VERSION 5.7 ;
BUSBITCHARS "[]" ;
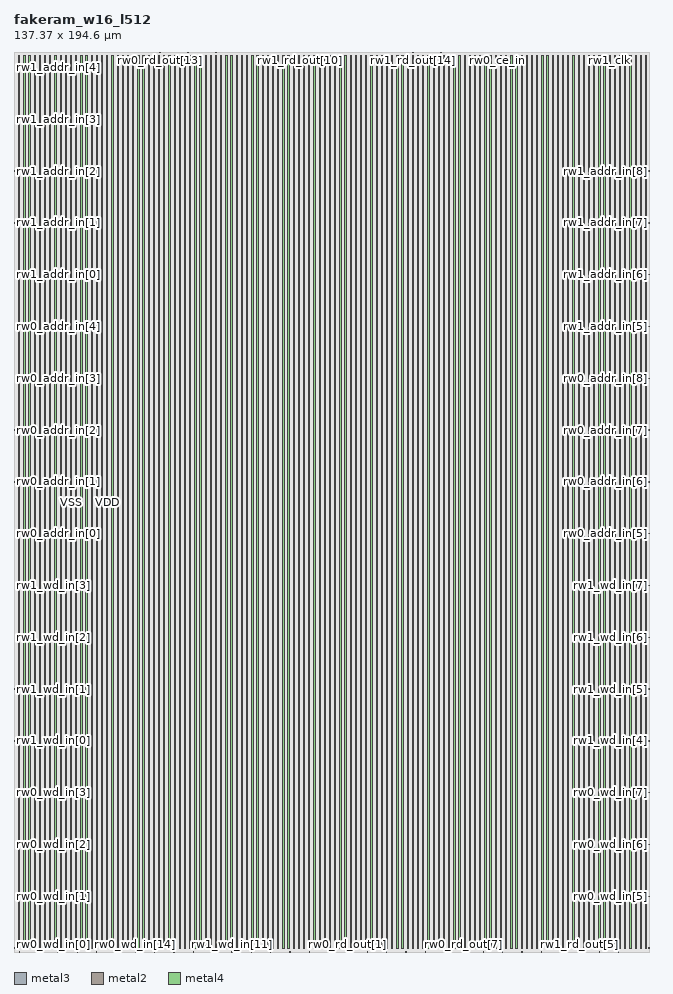
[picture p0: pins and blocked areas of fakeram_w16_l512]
MACRO fakeram_w16_l512
  FOREIGN fakeram_w16_l512 0 0 ;
  SYMMETRY X Y R90 ;
  SIZE 137.370 BY 194.600 ;
  CLASS BLOCK ;
  PIN rw0_wd_in[0]
    DIRECTION INPUT ;
    USE SIGNAL ;
    SHAPE ABUTMENT ;
    PORT
      LAYER metal3 ;
      RECT 0.000 0.805 0.210 0.875 ;
    END
  END rw0_wd_in[0]
  PIN rw0_wd_in[1]
    DIRECTION INPUT ;
    USE SIGNAL ;
    SHAPE ABUTMENT ;
    PORT
      LAYER metal3 ;
      RECT 0.000 12.005 0.210 12.075 ;
    END
  END rw0_wd_in[1]
  PIN rw0_wd_in[2]
    DIRECTION INPUT ;
    USE SIGNAL ;
    SHAPE ABUTMENT ;
    PORT
      LAYER metal3 ;
      RECT 0.000 23.205 0.210 23.275 ;
    END
  END rw0_wd_in[2]
  PIN rw0_wd_in[3]
    DIRECTION INPUT ;
    USE SIGNAL ;
    SHAPE ABUTMENT ;
    PORT
      LAYER metal3 ;
      RECT 0.000 34.405 0.210 34.475 ;
    END
  END rw0_wd_in[3]
  PIN rw0_wd_in[4]
    DIRECTION INPUT ;
    USE SIGNAL ;
    SHAPE ABUTMENT ;
    PORT
      LAYER metal3 ;
      RECT 137.160 0.805 137.370 0.875 ;
    END
  END rw0_wd_in[4]
  PIN rw0_wd_in[5]
    DIRECTION INPUT ;
    USE SIGNAL ;
    SHAPE ABUTMENT ;
    PORT
      LAYER metal3 ;
      RECT 137.160 12.005 137.370 12.075 ;
    END
  END rw0_wd_in[5]
  PIN rw0_wd_in[6]
    DIRECTION INPUT ;
    USE SIGNAL ;
    SHAPE ABUTMENT ;
    PORT
      LAYER metal3 ;
      RECT 137.160 23.205 137.370 23.275 ;
    END
  END rw0_wd_in[6]
  PIN rw0_wd_in[7]
    DIRECTION INPUT ;
    USE SIGNAL ;
    SHAPE ABUTMENT ;
    PORT
      LAYER metal3 ;
      RECT 137.160 34.405 137.370 34.475 ;
    END
  END rw0_wd_in[7]
  PIN rw0_wd_in[8]
    DIRECTION INPUT ;
    USE SIGNAL ;
    SHAPE ABUTMENT ;
    PORT
      LAYER metal2 ;
      RECT 1.105 0.000 1.175 0.210 ;
    END
  END rw0_wd_in[8]
  PIN rw0_wd_in[9]
    DIRECTION INPUT ;
    USE SIGNAL ;
    SHAPE ABUTMENT ;
    PORT
      LAYER metal2 ;
      RECT 5.285 0.000 5.355 0.210 ;
    END
  END rw0_wd_in[9]
  PIN rw0_wd_in[10]
    DIRECTION INPUT ;
    USE SIGNAL ;
    SHAPE ABUTMENT ;
    PORT
      LAYER metal2 ;
      RECT 9.465 0.000 9.535 0.210 ;
    END
  END rw0_wd_in[10]
  PIN rw0_wd_in[11]
    DIRECTION INPUT ;
    USE SIGNAL ;
    SHAPE ABUTMENT ;
    PORT
      LAYER metal2 ;
      RECT 13.645 0.000 13.715 0.210 ;
    END
  END rw0_wd_in[11]
  PIN rw0_wd_in[12]
    DIRECTION INPUT ;
    USE SIGNAL ;
    SHAPE ABUTMENT ;
    PORT
      LAYER metal2 ;
      RECT 17.825 0.000 17.895 0.210 ;
    END
  END rw0_wd_in[12]
  PIN rw0_wd_in[13]
    DIRECTION INPUT ;
    USE SIGNAL ;
    SHAPE ABUTMENT ;
    PORT
      LAYER metal2 ;
      RECT 22.005 0.000 22.075 0.210 ;
    END
  END rw0_wd_in[13]
  PIN rw0_wd_in[14]
    DIRECTION INPUT ;
    USE SIGNAL ;
    SHAPE ABUTMENT ;
    PORT
      LAYER metal2 ;
      RECT 26.185 0.000 26.255 0.210 ;
    END
  END rw0_wd_in[14]
  PIN rw0_wd_in[15]
    DIRECTION INPUT ;
    USE SIGNAL ;
    SHAPE ABUTMENT ;
    PORT
      LAYER metal2 ;
      RECT 30.365 0.000 30.435 0.210 ;
    END
  END rw0_wd_in[15]
  PIN rw1_wd_in[0]
    DIRECTION INPUT ;
    USE SIGNAL ;
    SHAPE ABUTMENT ;
    PORT
      LAYER metal3 ;
      RECT 0.000 45.605 0.210 45.675 ;
    END
  END rw1_wd_in[0]
  PIN rw1_wd_in[1]
    DIRECTION INPUT ;
    USE SIGNAL ;
    SHAPE ABUTMENT ;
    PORT
      LAYER metal3 ;
      RECT 0.000 56.805 0.210 56.875 ;
    END
  END rw1_wd_in[1]
  PIN rw1_wd_in[2]
    DIRECTION INPUT ;
    USE SIGNAL ;
    SHAPE ABUTMENT ;
    PORT
      LAYER metal3 ;
      RECT 0.000 68.005 0.210 68.075 ;
    END
  END rw1_wd_in[2]
  PIN rw1_wd_in[3]
    DIRECTION INPUT ;
    USE SIGNAL ;
    SHAPE ABUTMENT ;
    PORT
      LAYER metal3 ;
      RECT 0.000 79.205 0.210 79.275 ;
    END
  END rw1_wd_in[3]
  PIN rw1_wd_in[4]
    DIRECTION INPUT ;
    USE SIGNAL ;
    SHAPE ABUTMENT ;
    PORT
      LAYER metal3 ;
      RECT 137.160 45.605 137.370 45.675 ;
    END
  END rw1_wd_in[4]
  PIN rw1_wd_in[5]
    DIRECTION INPUT ;
    USE SIGNAL ;
    SHAPE ABUTMENT ;
    PORT
      LAYER metal3 ;
      RECT 137.160 56.805 137.370 56.875 ;
    END
  END rw1_wd_in[5]
  PIN rw1_wd_in[6]
    DIRECTION INPUT ;
    USE SIGNAL ;
    SHAPE ABUTMENT ;
    PORT
      LAYER metal3 ;
      RECT 137.160 68.005 137.370 68.075 ;
    END
  END rw1_wd_in[6]
  PIN rw1_wd_in[7]
    DIRECTION INPUT ;
    USE SIGNAL ;
    SHAPE ABUTMENT ;
    PORT
      LAYER metal3 ;
      RECT 137.160 79.205 137.370 79.275 ;
    END
  END rw1_wd_in[7]
  PIN rw1_wd_in[8]
    DIRECTION INPUT ;
    USE SIGNAL ;
    SHAPE ABUTMENT ;
    PORT
      LAYER metal2 ;
      RECT 34.545 0.000 34.615 0.210 ;
    END
  END rw1_wd_in[8]
  PIN rw1_wd_in[9]
    DIRECTION INPUT ;
    USE SIGNAL ;
    SHAPE ABUTMENT ;
    PORT
      LAYER metal2 ;
      RECT 38.725 0.000 38.795 0.210 ;
    END
  END rw1_wd_in[9]
  PIN rw1_wd_in[10]
    DIRECTION INPUT ;
    USE SIGNAL ;
    SHAPE ABUTMENT ;
    PORT
      LAYER metal2 ;
      RECT 42.905 0.000 42.975 0.210 ;
    END
  END rw1_wd_in[10]
  PIN rw1_wd_in[11]
    DIRECTION INPUT ;
    USE SIGNAL ;
    SHAPE ABUTMENT ;
    PORT
      LAYER metal2 ;
      RECT 47.085 0.000 47.155 0.210 ;
    END
  END rw1_wd_in[11]
  PIN rw1_wd_in[12]
    DIRECTION INPUT ;
    USE SIGNAL ;
    SHAPE ABUTMENT ;
    PORT
      LAYER metal2 ;
      RECT 51.265 0.000 51.335 0.210 ;
    END
  END rw1_wd_in[12]
  PIN rw1_wd_in[13]
    DIRECTION INPUT ;
    USE SIGNAL ;
    SHAPE ABUTMENT ;
    PORT
      LAYER metal2 ;
      RECT 55.445 0.000 55.515 0.210 ;
    END
  END rw1_wd_in[13]
  PIN rw1_wd_in[14]
    DIRECTION INPUT ;
    USE SIGNAL ;
    SHAPE ABUTMENT ;
    PORT
      LAYER metal2 ;
      RECT 59.625 0.000 59.695 0.210 ;
    END
  END rw1_wd_in[14]
  PIN rw1_wd_in[15]
    DIRECTION INPUT ;
    USE SIGNAL ;
    SHAPE ABUTMENT ;
    PORT
      LAYER metal2 ;
      RECT 63.805 0.000 63.875 0.210 ;
    END
  END rw1_wd_in[15]
  PIN rw0_rd_out[0]
    DIRECTION OUTPUT ;
    USE SIGNAL ;
    SHAPE ABUTMENT ;
    PORT
      LAYER metal2 ;
      RECT 67.985 0.000 68.055 0.210 ;
    END
  END rw0_rd_out[0]
  PIN rw0_rd_out[1]
    DIRECTION OUTPUT ;
    USE SIGNAL ;
    SHAPE ABUTMENT ;
    PORT
      LAYER metal2 ;
      RECT 72.165 0.000 72.235 0.210 ;
    END
  END rw0_rd_out[1]
  PIN rw0_rd_out[2]
    DIRECTION OUTPUT ;
    USE SIGNAL ;
    SHAPE ABUTMENT ;
    PORT
      LAYER metal2 ;
      RECT 76.345 0.000 76.415 0.210 ;
    END
  END rw0_rd_out[2]
  PIN rw0_rd_out[3]
    DIRECTION OUTPUT ;
    USE SIGNAL ;
    SHAPE ABUTMENT ;
    PORT
      LAYER metal2 ;
      RECT 80.525 0.000 80.595 0.210 ;
    END
  END rw0_rd_out[3]
  PIN rw0_rd_out[4]
    DIRECTION OUTPUT ;
    USE SIGNAL ;
    SHAPE ABUTMENT ;
    PORT
      LAYER metal2 ;
      RECT 84.705 0.000 84.775 0.210 ;
    END
  END rw0_rd_out[4]
  PIN rw0_rd_out[5]
    DIRECTION OUTPUT ;
    USE SIGNAL ;
    SHAPE ABUTMENT ;
    PORT
      LAYER metal2 ;
      RECT 88.885 0.000 88.955 0.210 ;
    END
  END rw0_rd_out[5]
  PIN rw0_rd_out[6]
    DIRECTION OUTPUT ;
    USE SIGNAL ;
    SHAPE ABUTMENT ;
    PORT
      LAYER metal2 ;
      RECT 93.065 0.000 93.135 0.210 ;
    END
  END rw0_rd_out[6]
  PIN rw0_rd_out[7]
    DIRECTION OUTPUT ;
    USE SIGNAL ;
    SHAPE ABUTMENT ;
    PORT
      LAYER metal2 ;
      RECT 97.245 0.000 97.315 0.210 ;
    END
  END rw0_rd_out[7]
  PIN rw0_rd_out[8]
    DIRECTION OUTPUT ;
    USE SIGNAL ;
    SHAPE ABUTMENT ;
    PORT
      LAYER metal2 ;
      RECT 1.105 194.390 1.175 194.600 ;
    END
  END rw0_rd_out[8]
  PIN rw0_rd_out[9]
    DIRECTION OUTPUT ;
    USE SIGNAL ;
    SHAPE ABUTMENT ;
    PORT
      LAYER metal2 ;
      RECT 7.185 194.390 7.255 194.600 ;
    END
  END rw0_rd_out[9]
  PIN rw0_rd_out[10]
    DIRECTION OUTPUT ;
    USE SIGNAL ;
    SHAPE ABUTMENT ;
    PORT
      LAYER metal2 ;
      RECT 13.265 194.390 13.335 194.600 ;
    END
  END rw0_rd_out[10]
  PIN rw0_rd_out[11]
    DIRECTION OUTPUT ;
    USE SIGNAL ;
    SHAPE ABUTMENT ;
    PORT
      LAYER metal2 ;
      RECT 19.345 194.390 19.415 194.600 ;
    END
  END rw0_rd_out[11]
  PIN rw0_rd_out[12]
    DIRECTION OUTPUT ;
    USE SIGNAL ;
    SHAPE ABUTMENT ;
    PORT
      LAYER metal2 ;
      RECT 25.425 194.390 25.495 194.600 ;
    END
  END rw0_rd_out[12]
  PIN rw0_rd_out[13]
    DIRECTION OUTPUT ;
    USE SIGNAL ;
    SHAPE ABUTMENT ;
    PORT
      LAYER metal2 ;
      RECT 31.505 194.390 31.575 194.600 ;
    END
  END rw0_rd_out[13]
  PIN rw0_rd_out[14]
    DIRECTION OUTPUT ;
    USE SIGNAL ;
    SHAPE ABUTMENT ;
    PORT
      LAYER metal2 ;
      RECT 37.585 194.390 37.655 194.600 ;
    END
  END rw0_rd_out[14]
  PIN rw0_rd_out[15]
    DIRECTION OUTPUT ;
    USE SIGNAL ;
    SHAPE ABUTMENT ;
    PORT
      LAYER metal2 ;
      RECT 43.665 194.390 43.735 194.600 ;
    END
  END rw0_rd_out[15]
  PIN rw1_rd_out[0]
    DIRECTION OUTPUT ;
    USE SIGNAL ;
    SHAPE ABUTMENT ;
    PORT
      LAYER metal2 ;
      RECT 101.425 0.000 101.495 0.210 ;
    END
  END rw1_rd_out[0]
  PIN rw1_rd_out[1]
    DIRECTION OUTPUT ;
    USE SIGNAL ;
    SHAPE ABUTMENT ;
    PORT
      LAYER metal2 ;
      RECT 105.605 0.000 105.675 0.210 ;
    END
  END rw1_rd_out[1]
  PIN rw1_rd_out[2]
    DIRECTION OUTPUT ;
    USE SIGNAL ;
    SHAPE ABUTMENT ;
    PORT
      LAYER metal2 ;
      RECT 109.785 0.000 109.855 0.210 ;
    END
  END rw1_rd_out[2]
  PIN rw1_rd_out[3]
    DIRECTION OUTPUT ;
    USE SIGNAL ;
    SHAPE ABUTMENT ;
    PORT
      LAYER metal2 ;
      RECT 113.965 0.000 114.035 0.210 ;
    END
  END rw1_rd_out[3]
  PIN rw1_rd_out[4]
    DIRECTION OUTPUT ;
    USE SIGNAL ;
    SHAPE ABUTMENT ;
    PORT
      LAYER metal2 ;
      RECT 118.145 0.000 118.215 0.210 ;
    END
  END rw1_rd_out[4]
  PIN rw1_rd_out[5]
    DIRECTION OUTPUT ;
    USE SIGNAL ;
    SHAPE ABUTMENT ;
    PORT
      LAYER metal2 ;
      RECT 122.325 0.000 122.395 0.210 ;
    END
  END rw1_rd_out[5]
  PIN rw1_rd_out[6]
    DIRECTION OUTPUT ;
    USE SIGNAL ;
    SHAPE ABUTMENT ;
    PORT
      LAYER metal2 ;
      RECT 126.505 0.000 126.575 0.210 ;
    END
  END rw1_rd_out[6]
  PIN rw1_rd_out[7]
    DIRECTION OUTPUT ;
    USE SIGNAL ;
    SHAPE ABUTMENT ;
    PORT
      LAYER metal2 ;
      RECT 130.685 0.000 130.755 0.210 ;
    END
  END rw1_rd_out[7]
  PIN rw1_rd_out[8]
    DIRECTION OUTPUT ;
    USE SIGNAL ;
    SHAPE ABUTMENT ;
    PORT
      LAYER metal2 ;
      RECT 49.745 194.390 49.815 194.600 ;
    END
  END rw1_rd_out[8]
  PIN rw1_rd_out[9]
    DIRECTION OUTPUT ;
    USE SIGNAL ;
    SHAPE ABUTMENT ;
    PORT
      LAYER metal2 ;
      RECT 55.825 194.390 55.895 194.600 ;
    END
  END rw1_rd_out[9]
  PIN rw1_rd_out[10]
    DIRECTION OUTPUT ;
    USE SIGNAL ;
    SHAPE ABUTMENT ;
    PORT
      LAYER metal2 ;
      RECT 61.905 194.390 61.975 194.600 ;
    END
  END rw1_rd_out[10]
  PIN rw1_rd_out[11]
    DIRECTION OUTPUT ;
    USE SIGNAL ;
    SHAPE ABUTMENT ;
    PORT
      LAYER metal2 ;
      RECT 67.985 194.390 68.055 194.600 ;
    END
  END rw1_rd_out[11]
  PIN rw1_rd_out[12]
    DIRECTION OUTPUT ;
    USE SIGNAL ;
    SHAPE ABUTMENT ;
    PORT
      LAYER metal2 ;
      RECT 74.065 194.390 74.135 194.600 ;
    END
  END rw1_rd_out[12]
  PIN rw1_rd_out[13]
    DIRECTION OUTPUT ;
    USE SIGNAL ;
    SHAPE ABUTMENT ;
    PORT
      LAYER metal2 ;
      RECT 80.145 194.390 80.215 194.600 ;
    END
  END rw1_rd_out[13]
  PIN rw1_rd_out[14]
    DIRECTION OUTPUT ;
    USE SIGNAL ;
    SHAPE ABUTMENT ;
    PORT
      LAYER metal2 ;
      RECT 86.225 194.390 86.295 194.600 ;
    END
  END rw1_rd_out[14]
  PIN rw1_rd_out[15]
    DIRECTION OUTPUT ;
    USE SIGNAL ;
    SHAPE ABUTMENT ;
    PORT
      LAYER metal2 ;
      RECT 92.305 194.390 92.375 194.600 ;
    END
  END rw1_rd_out[15]
  PIN rw0_addr_in[0]
    DIRECTION INPUT ;
    USE SIGNAL ;
    SHAPE ABUTMENT ;
    PORT
      LAYER metal3 ;
      RECT 0.000 90.405 0.210 90.475 ;
    END
  END rw0_addr_in[0]
  PIN rw0_addr_in[1]
    DIRECTION INPUT ;
    USE SIGNAL ;
    SHAPE ABUTMENT ;
    PORT
      LAYER metal3 ;
      RECT 0.000 101.605 0.210 101.675 ;
    END
  END rw0_addr_in[1]
  PIN rw0_addr_in[2]
    DIRECTION INPUT ;
    USE SIGNAL ;
    SHAPE ABUTMENT ;
    PORT
      LAYER metal3 ;
      RECT 0.000 112.805 0.210 112.875 ;
    END
  END rw0_addr_in[2]
  PIN rw0_addr_in[3]
    DIRECTION INPUT ;
    USE SIGNAL ;
    SHAPE ABUTMENT ;
    PORT
      LAYER metal3 ;
      RECT 0.000 124.005 0.210 124.075 ;
    END
  END rw0_addr_in[3]
  PIN rw0_addr_in[4]
    DIRECTION INPUT ;
    USE SIGNAL ;
    SHAPE ABUTMENT ;
    PORT
      LAYER metal3 ;
      RECT 0.000 135.205 0.210 135.275 ;
    END
  END rw0_addr_in[4]
  PIN rw0_addr_in[5]
    DIRECTION INPUT ;
    USE SIGNAL ;
    SHAPE ABUTMENT ;
    PORT
      LAYER metal3 ;
      RECT 137.160 90.405 137.370 90.475 ;
    END
  END rw0_addr_in[5]
  PIN rw0_addr_in[6]
    DIRECTION INPUT ;
    USE SIGNAL ;
    SHAPE ABUTMENT ;
    PORT
      LAYER metal3 ;
      RECT 137.160 101.605 137.370 101.675 ;
    END
  END rw0_addr_in[6]
  PIN rw0_addr_in[7]
    DIRECTION INPUT ;
    USE SIGNAL ;
    SHAPE ABUTMENT ;
    PORT
      LAYER metal3 ;
      RECT 137.160 112.805 137.370 112.875 ;
    END
  END rw0_addr_in[7]
  PIN rw0_addr_in[8]
    DIRECTION INPUT ;
    USE SIGNAL ;
    SHAPE ABUTMENT ;
    PORT
      LAYER metal3 ;
      RECT 137.160 124.005 137.370 124.075 ;
    END
  END rw0_addr_in[8]
  PIN rw1_addr_in[0]
    DIRECTION INPUT ;
    USE SIGNAL ;
    SHAPE ABUTMENT ;
    PORT
      LAYER metal3 ;
      RECT 0.000 146.405 0.210 146.475 ;
    END
  END rw1_addr_in[0]
  PIN rw1_addr_in[1]
    DIRECTION INPUT ;
    USE SIGNAL ;
    SHAPE ABUTMENT ;
    PORT
      LAYER metal3 ;
      RECT 0.000 157.605 0.210 157.675 ;
    END
  END rw1_addr_in[1]
  PIN rw1_addr_in[2]
    DIRECTION INPUT ;
    USE SIGNAL ;
    SHAPE ABUTMENT ;
    PORT
      LAYER metal3 ;
      RECT 0.000 168.805 0.210 168.875 ;
    END
  END rw1_addr_in[2]
  PIN rw1_addr_in[3]
    DIRECTION INPUT ;
    USE SIGNAL ;
    SHAPE ABUTMENT ;
    PORT
      LAYER metal3 ;
      RECT 0.000 180.005 0.210 180.075 ;
    END
  END rw1_addr_in[3]
  PIN rw1_addr_in[4]
    DIRECTION INPUT ;
    USE SIGNAL ;
    SHAPE ABUTMENT ;
    PORT
      LAYER metal3 ;
      RECT 0.000 191.205 0.210 191.275 ;
    END
  END rw1_addr_in[4]
  PIN rw1_addr_in[5]
    DIRECTION INPUT ;
    USE SIGNAL ;
    SHAPE ABUTMENT ;
    PORT
      LAYER metal3 ;
      RECT 137.160 135.205 137.370 135.275 ;
    END
  END rw1_addr_in[5]
  PIN rw1_addr_in[6]
    DIRECTION INPUT ;
    USE SIGNAL ;
    SHAPE ABUTMENT ;
    PORT
      LAYER metal3 ;
      RECT 137.160 146.405 137.370 146.475 ;
    END
  END rw1_addr_in[6]
  PIN rw1_addr_in[7]
    DIRECTION INPUT ;
    USE SIGNAL ;
    SHAPE ABUTMENT ;
    PORT
      LAYER metal3 ;
      RECT 137.160 157.605 137.370 157.675 ;
    END
  END rw1_addr_in[7]
  PIN rw1_addr_in[8]
    DIRECTION INPUT ;
    USE SIGNAL ;
    SHAPE ABUTMENT ;
    PORT
      LAYER metal3 ;
      RECT 137.160 168.805 137.370 168.875 ;
    END
  END rw1_addr_in[8]
  PIN rw0_we_in
    DIRECTION INPUT ;
    USE SIGNAL ;
    SHAPE ABUTMENT ;
    PORT
      LAYER metal2 ;
      RECT 98.385 194.390 98.455 194.600 ;
    END
  END rw0_we_in
  PIN rw0_ce_in
    DIRECTION INPUT ;
    USE SIGNAL ;
    SHAPE ABUTMENT ;
    PORT
      LAYER metal2 ;
      RECT 104.465 194.390 104.535 194.600 ;
    END
  END rw0_ce_in
  PIN rw0_clk
    DIRECTION INPUT ;
    USE SIGNAL ;
    SHAPE ABUTMENT ;
    PORT
      LAYER metal2 ;
      RECT 110.545 194.390 110.615 194.600 ;
    END
  END rw0_clk
  PIN rw1_we_in
    DIRECTION INPUT ;
    USE SIGNAL ;
    SHAPE ABUTMENT ;
    PORT
      LAYER metal2 ;
      RECT 116.625 194.390 116.695 194.600 ;
    END
  END rw1_we_in
  PIN rw1_ce_in
    DIRECTION INPUT ;
    USE SIGNAL ;
    SHAPE ABUTMENT ;
    PORT
      LAYER metal2 ;
      RECT 122.705 194.390 122.775 194.600 ;
    END
  END rw1_ce_in
  PIN rw1_clk
    DIRECTION INPUT ;
    USE SIGNAL ;
    SHAPE ABUTMENT ;
    PORT
      LAYER metal2 ;
      RECT 128.785 194.390 128.855 194.600 ;
    END
  END rw1_clk
  PIN VSS
    DIRECTION INOUT ;
    USE GROUND ;
    PORT
      LAYER metal4 ;
      RECT 1.000 0.840 1.280 193.760 ;
      RECT 3.240 0.840 3.520 193.760 ;
      RECT 5.480 0.840 5.760 193.760 ;
      RECT 7.720 0.840 8.000 193.760 ;
      RECT 9.960 0.840 10.240 193.760 ;
      RECT 12.200 0.840 12.480 193.760 ;
      RECT 14.440 0.840 14.720 193.760 ;
      RECT 16.680 0.840 16.960 193.760 ;
      RECT 18.920 0.840 19.200 193.760 ;
      RECT 21.160 0.840 21.440 193.760 ;
      RECT 23.400 0.840 23.680 193.760 ;
      RECT 25.640 0.840 25.920 193.760 ;
      RECT 27.880 0.840 28.160 193.760 ;
      RECT 30.120 0.840 30.400 193.760 ;
      RECT 32.360 0.840 32.640 193.760 ;
      RECT 34.600 0.840 34.880 193.760 ;
      RECT 36.840 0.840 37.120 193.760 ;
      RECT 39.080 0.840 39.360 193.760 ;
      RECT 41.320 0.840 41.600 193.760 ;
      RECT 43.560 0.840 43.840 193.760 ;
      RECT 45.800 0.840 46.080 193.760 ;
      RECT 48.040 0.840 48.320 193.760 ;
      RECT 50.280 0.840 50.560 193.760 ;
      RECT 52.520 0.840 52.800 193.760 ;
      RECT 54.760 0.840 55.040 193.760 ;
      RECT 57.000 0.840 57.280 193.760 ;
      RECT 59.240 0.840 59.520 193.760 ;
      RECT 61.480 0.840 61.760 193.760 ;
      RECT 63.720 0.840 64.000 193.760 ;
      RECT 65.960 0.840 66.240 193.760 ;
      RECT 68.200 0.840 68.480 193.760 ;
      RECT 70.440 0.840 70.720 193.760 ;
      RECT 72.680 0.840 72.960 193.760 ;
      RECT 74.920 0.840 75.200 193.760 ;
      RECT 77.160 0.840 77.440 193.760 ;
      RECT 79.400 0.840 79.680 193.760 ;
      RECT 81.640 0.840 81.920 193.760 ;
      RECT 83.880 0.840 84.160 193.760 ;
      RECT 86.120 0.840 86.400 193.760 ;
      RECT 88.360 0.840 88.640 193.760 ;
      RECT 90.600 0.840 90.880 193.760 ;
      RECT 92.840 0.840 93.120 193.760 ;
      RECT 95.080 0.840 95.360 193.760 ;
      RECT 97.320 0.840 97.600 193.760 ;
      RECT 99.560 0.840 99.840 193.760 ;
      RECT 101.800 0.840 102.080 193.760 ;
      RECT 104.040 0.840 104.320 193.760 ;
      RECT 106.280 0.840 106.560 193.760 ;
      RECT 108.520 0.840 108.800 193.760 ;
      RECT 110.760 0.840 111.040 193.760 ;
      RECT 113.000 0.840 113.280 193.760 ;
      RECT 115.240 0.840 115.520 193.760 ;
      RECT 117.480 0.840 117.760 193.760 ;
      RECT 119.720 0.840 120.000 193.760 ;
      RECT 121.960 0.840 122.240 193.760 ;
      RECT 124.200 0.840 124.480 193.760 ;
      RECT 126.440 0.840 126.720 193.760 ;
      RECT 128.680 0.840 128.960 193.760 ;
      RECT 130.920 0.840 131.200 193.760 ;
      RECT 133.160 0.840 133.440 193.760 ;
      RECT 135.400 0.840 135.680 193.760 ;
    END
  END VSS
  PIN VDD
    DIRECTION INOUT ;
    USE POWER ;
    PORT
      LAYER metal4 ;
      RECT 2.120 0.840 2.400 193.760 ;
      RECT 4.360 0.840 4.640 193.760 ;
      RECT 6.600 0.840 6.880 193.760 ;
      RECT 8.840 0.840 9.120 193.760 ;
      RECT 11.080 0.840 11.360 193.760 ;
      RECT 13.320 0.840 13.600 193.760 ;
      RECT 15.560 0.840 15.840 193.760 ;
      RECT 17.800 0.840 18.080 193.760 ;
      RECT 20.040 0.840 20.320 193.760 ;
      RECT 22.280 0.840 22.560 193.760 ;
      RECT 24.520 0.840 24.800 193.760 ;
      RECT 26.760 0.840 27.040 193.760 ;
      RECT 29.000 0.840 29.280 193.760 ;
      RECT 31.240 0.840 31.520 193.760 ;
      RECT 33.480 0.840 33.760 193.760 ;
      RECT 35.720 0.840 36.000 193.760 ;
      RECT 37.960 0.840 38.240 193.760 ;
      RECT 40.200 0.840 40.480 193.760 ;
      RECT 42.440 0.840 42.720 193.760 ;
      RECT 44.680 0.840 44.960 193.760 ;
      RECT 46.920 0.840 47.200 193.760 ;
      RECT 49.160 0.840 49.440 193.760 ;
      RECT 51.400 0.840 51.680 193.760 ;
      RECT 53.640 0.840 53.920 193.760 ;
      RECT 55.880 0.840 56.160 193.760 ;
      RECT 58.120 0.840 58.400 193.760 ;
      RECT 60.360 0.840 60.640 193.760 ;
      RECT 62.600 0.840 62.880 193.760 ;
      RECT 64.840 0.840 65.120 193.760 ;
      RECT 67.080 0.840 67.360 193.760 ;
      RECT 69.320 0.840 69.600 193.760 ;
      RECT 71.560 0.840 71.840 193.760 ;
      RECT 73.800 0.840 74.080 193.760 ;
      RECT 76.040 0.840 76.320 193.760 ;
      RECT 78.280 0.840 78.560 193.760 ;
      RECT 80.520 0.840 80.800 193.760 ;
      RECT 82.760 0.840 83.040 193.760 ;
      RECT 85.000 0.840 85.280 193.760 ;
      RECT 87.240 0.840 87.520 193.760 ;
      RECT 89.480 0.840 89.760 193.760 ;
      RECT 91.720 0.840 92.000 193.760 ;
      RECT 93.960 0.840 94.240 193.760 ;
      RECT 96.200 0.840 96.480 193.760 ;
      RECT 98.440 0.840 98.720 193.760 ;
      RECT 100.680 0.840 100.960 193.760 ;
      RECT 102.920 0.840 103.200 193.760 ;
      RECT 105.160 0.840 105.440 193.760 ;
      RECT 107.400 0.840 107.680 193.760 ;
      RECT 109.640 0.840 109.920 193.760 ;
      RECT 111.880 0.840 112.160 193.760 ;
      RECT 114.120 0.840 114.400 193.760 ;
      RECT 116.360 0.840 116.640 193.760 ;
      RECT 118.600 0.840 118.880 193.760 ;
      RECT 120.840 0.840 121.120 193.760 ;
      RECT 123.080 0.840 123.360 193.760 ;
      RECT 125.320 0.840 125.600 193.760 ;
      RECT 127.560 0.840 127.840 193.760 ;
      RECT 129.800 0.840 130.080 193.760 ;
      RECT 132.040 0.840 132.320 193.760 ;
      RECT 134.280 0.840 134.560 193.760 ;
      RECT 136.520 0.840 136.800 193.760 ;
    END
  END VDD
  OBS
    LAYER metal1 ;
    RECT 0 0 137.370 194.600 ;
    LAYER metal2 ;
    RECT 0 0 137.370 194.600 ;
    LAYER metal3 ;
    RECT 0 0 137.370 194.600 ;
    LAYER metal4 ;
    RECT 0 0 137.370 194.600 ;
    LAYER OVERLAP ;
    RECT 0 0 137.370 194.600 ;
  END
END fakeram_w16_l512

END LIBRARY
